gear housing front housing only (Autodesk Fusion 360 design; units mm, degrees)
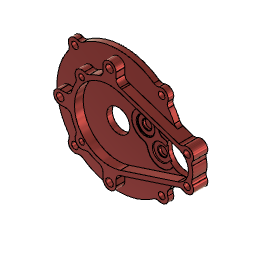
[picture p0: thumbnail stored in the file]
derived_base_feature "Derived Base Feature" bodies "Front Housing"
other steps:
create_component "CreateComponent1"
named bodies: "Front Housing"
